VERSION 5.7 ;
  NOWIREEXTENSIONATPIN ON ;
  DIVIDERCHAR "/" ;
  BUSBITCHARS "[]" ;
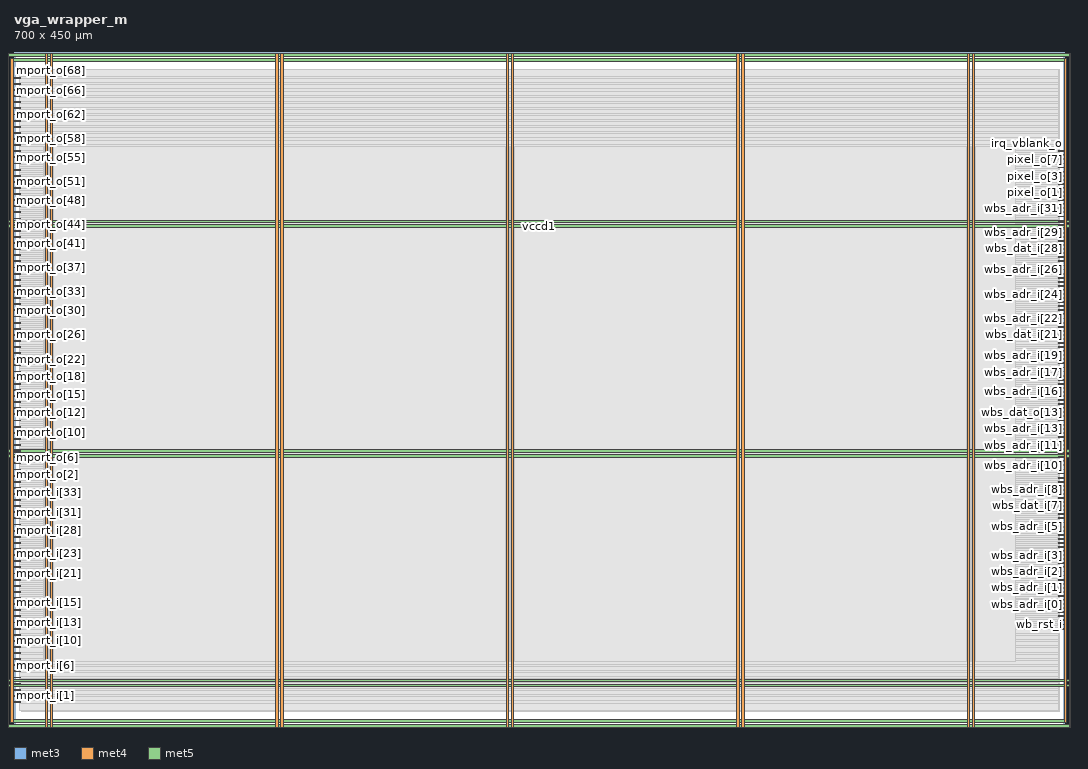
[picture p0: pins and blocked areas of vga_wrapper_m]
MACRO vga_wrapper_m
  CLASS BLOCK ;
  FOREIGN vga_wrapper_m ;
  ORIGIN 0.000 0.000 ;
  SIZE 700.000 BY 450.000 ;
  PIN hsync_o
    DIRECTION OUTPUT TRISTATE ;
    USE SIGNAL ;
    ANTENNADIFFAREA 0.445500 ;
    PORT
      LAYER met3 ;
        RECT 696.000 375.400 700.000 376.000 ;
    END
  END hsync_o
  PIN irq_hblank_o
    DIRECTION OUTPUT TRISTATE ;
    USE SIGNAL ;
    ANTENNADIFFAREA 0.445500 ;
    PORT
      LAYER met3 ;
        RECT 696.000 380.840 700.000 381.440 ;
    END
  END irq_hblank_o
  PIN irq_vblank_o
    DIRECTION OUTPUT TRISTATE ;
    USE SIGNAL ;
    ANTENNADIFFAREA 0.445500 ;
    PORT
      LAYER met3 ;
        RECT 696.000 383.560 700.000 384.160 ;
    END
  END irq_vblank_o
  PIN mport_i[0]
    DIRECTION INPUT ;
    USE SIGNAL ;
    ANTENNAGATEAREA 0.495000 ;
    PORT
      LAYER met3 ;
        RECT 0.000 16.360 4.000 16.960 ;
    END
  END mport_i[0]
  PIN mport_i[10]
    DIRECTION INPUT ;
    USE SIGNAL ;
    ANTENNAGATEAREA 0.247500 ;
    PORT
      LAYER met3 ;
        RECT 0.000 57.160 4.000 57.760 ;
    END
  END mport_i[10]
  PIN mport_i[11]
    DIRECTION INPUT ;
    USE SIGNAL ;
    ANTENNAGATEAREA 0.247500 ;
    PORT
      LAYER met3 ;
        RECT 0.000 61.240 4.000 61.840 ;
    END
  END mport_i[11]
  PIN mport_i[12]
    DIRECTION INPUT ;
    USE SIGNAL ;
    ANTENNAGATEAREA 0.426000 ;
    PORT
      LAYER met3 ;
        RECT 0.000 65.320 4.000 65.920 ;
    END
  END mport_i[12]
  PIN mport_i[13]
    DIRECTION INPUT ;
    USE SIGNAL ;
    ANTENNAGATEAREA 0.495000 ;
    PORT
      LAYER met3 ;
        RECT 0.000 69.400 4.000 70.000 ;
    END
  END mport_i[13]
  PIN mport_i[14]
    DIRECTION INPUT ;
    USE SIGNAL ;
    ANTENNAGATEAREA 0.247500 ;
    PORT
      LAYER met3 ;
        RECT 0.000 73.480 4.000 74.080 ;
    END
  END mport_i[14]
  PIN mport_i[15]
    DIRECTION INPUT ;
    USE SIGNAL ;
    ANTENNAGATEAREA 0.196500 ;
    PORT
      LAYER met3 ;
        RECT 0.000 77.560 4.000 78.160 ;
    END
  END mport_i[15]
  PIN mport_i[16]
    DIRECTION INPUT ;
    USE SIGNAL ;
    ANTENNAGATEAREA 0.196500 ;
    PORT
      LAYER met3 ;
        RECT 0.000 81.640 4.000 82.240 ;
    END
  END mport_i[16]
  PIN mport_i[17]
    DIRECTION INPUT ;
    USE SIGNAL ;
    ANTENNAGATEAREA 0.196500 ;
    PORT
      LAYER met3 ;
        RECT 0.000 85.720 4.000 86.320 ;
    END
  END mport_i[17]
  PIN mport_i[18]
    DIRECTION INPUT ;
    USE SIGNAL ;
    ANTENNAGATEAREA 0.196500 ;
    PORT
      LAYER met3 ;
        RECT 0.000 89.800 4.000 90.400 ;
    END
  END mport_i[18]
  PIN mport_i[19]
    DIRECTION INPUT ;
    USE SIGNAL ;
    ANTENNAGATEAREA 0.196500 ;
    PORT
      LAYER met3 ;
        RECT 0.000 93.880 4.000 94.480 ;
    END
  END mport_i[19]
  PIN mport_i[1]
    DIRECTION INPUT ;
    USE SIGNAL ;
    ANTENNAGATEAREA 0.426000 ;
    PORT
      LAYER met3 ;
        RECT 0.000 20.440 4.000 21.040 ;
    END
  END mport_i[1]
  PIN mport_i[20]
    DIRECTION INPUT ;
    USE SIGNAL ;
    ANTENNAGATEAREA 0.247500 ;
    PORT
      LAYER met3 ;
        RECT 0.000 97.960 4.000 98.560 ;
    END
  END mport_i[20]
  PIN mport_i[21]
    DIRECTION INPUT ;
    USE SIGNAL ;
    ANTENNAGATEAREA 0.196500 ;
    PORT
      LAYER met3 ;
        RECT 0.000 102.040 4.000 102.640 ;
    END
  END mport_i[21]
  PIN mport_i[22]
    DIRECTION INPUT ;
    USE SIGNAL ;
    ANTENNAGATEAREA 0.196500 ;
    PORT
      LAYER met3 ;
        RECT 0.000 106.120 4.000 106.720 ;
    END
  END mport_i[22]
  PIN mport_i[23]
    DIRECTION INPUT ;
    USE SIGNAL ;
    ANTENNAGATEAREA 0.426000 ;
    PORT
      LAYER met3 ;
        RECT 0.000 110.200 4.000 110.800 ;
    END
  END mport_i[23]
  PIN mport_i[24]
    DIRECTION INPUT ;
    USE SIGNAL ;
    ANTENNAGATEAREA 0.213000 ;
    PORT
      LAYER met3 ;
        RECT 0.000 114.280 4.000 114.880 ;
    END
  END mport_i[24]
  PIN mport_i[25]
    DIRECTION INPUT ;
    USE SIGNAL ;
    ANTENNAGATEAREA 0.426000 ;
    PORT
      LAYER met3 ;
        RECT 0.000 118.360 4.000 118.960 ;
    END
  END mport_i[25]
  PIN mport_i[26]
    DIRECTION INPUT ;
    USE SIGNAL ;
    ANTENNAGATEAREA 0.426000 ;
    PORT
      LAYER met3 ;
        RECT 0.000 122.440 4.000 123.040 ;
    END
  END mport_i[26]
  PIN mport_i[27]
    DIRECTION INPUT ;
    USE SIGNAL ;
    ANTENNAGATEAREA 0.196500 ;
    PORT
      LAYER met3 ;
        RECT 0.000 126.520 4.000 127.120 ;
    END
  END mport_i[27]
  PIN mport_i[28]
    DIRECTION INPUT ;
    USE SIGNAL ;
    ANTENNAGATEAREA 0.426000 ;
    PORT
      LAYER met3 ;
        RECT 0.000 130.600 4.000 131.200 ;
    END
  END mport_i[28]
  PIN mport_i[29]
    DIRECTION INPUT ;
    USE SIGNAL ;
    ANTENNAGATEAREA 0.196500 ;
    PORT
      LAYER met3 ;
        RECT 0.000 134.680 4.000 135.280 ;
    END
  END mport_i[29]
  PIN mport_i[2]
    DIRECTION INPUT ;
    USE SIGNAL ;
    ANTENNAGATEAREA 0.126000 ;
    PORT
      LAYER met3 ;
        RECT 0.000 24.520 4.000 25.120 ;
    END
  END mport_i[2]
  PIN mport_i[30]
    DIRECTION INPUT ;
    USE SIGNAL ;
    ANTENNAGATEAREA 0.126000 ;
    PORT
      LAYER met3 ;
        RECT 0.000 138.760 4.000 139.360 ;
    END
  END mport_i[30]
  PIN mport_i[31]
    DIRECTION INPUT ;
    USE SIGNAL ;
    ANTENNAGATEAREA 0.196500 ;
    PORT
      LAYER met3 ;
        RECT 0.000 142.840 4.000 143.440 ;
    END
  END mport_i[31]
  PIN mport_i[32]
    DIRECTION INPUT ;
    USE SIGNAL ;
    ANTENNAGATEAREA 0.247500 ;
    PORT
      LAYER met3 ;
        RECT 0.000 146.920 4.000 147.520 ;
    END
  END mport_i[32]
  PIN mport_i[33]
    DIRECTION INPUT ;
    USE SIGNAL ;
    ANTENNAGATEAREA 0.213000 ;
    PORT
      LAYER met3 ;
        RECT 0.000 151.000 4.000 151.600 ;
    END
  END mport_i[33]
  PIN mport_i[3]
    DIRECTION INPUT ;
    USE SIGNAL ;
    ANTENNAGATEAREA 0.196500 ;
    PORT
      LAYER met3 ;
        RECT 0.000 28.600 4.000 29.200 ;
    END
  END mport_i[3]
  PIN mport_i[4]
    DIRECTION INPUT ;
    USE SIGNAL ;
    ANTENNAGATEAREA 0.196500 ;
    PORT
      LAYER met3 ;
        RECT 0.000 32.680 4.000 33.280 ;
    END
  END mport_i[4]
  PIN mport_i[5]
    DIRECTION INPUT ;
    USE SIGNAL ;
    ANTENNAGATEAREA 0.495000 ;
    PORT
      LAYER met3 ;
        RECT 0.000 36.760 4.000 37.360 ;
    END
  END mport_i[5]
  PIN mport_i[6]
    DIRECTION INPUT ;
    USE SIGNAL ;
    ANTENNAGATEAREA 0.196500 ;
    PORT
      LAYER met3 ;
        RECT 0.000 40.840 4.000 41.440 ;
    END
  END mport_i[6]
  PIN mport_i[7]
    DIRECTION INPUT ;
    USE SIGNAL ;
    ANTENNAGATEAREA 0.196500 ;
    PORT
      LAYER met3 ;
        RECT 0.000 44.920 4.000 45.520 ;
    END
  END mport_i[7]
  PIN mport_i[8]
    DIRECTION INPUT ;
    USE SIGNAL ;
    ANTENNAGATEAREA 0.247500 ;
    PORT
      LAYER met3 ;
        RECT 0.000 49.000 4.000 49.600 ;
    END
  END mport_i[8]
  PIN mport_i[9]
    DIRECTION INPUT ;
    USE SIGNAL ;
    ANTENNAGATEAREA 0.196500 ;
    PORT
      LAYER met3 ;
        RECT 0.000 53.080 4.000 53.680 ;
    END
  END mport_i[9]
  PIN mport_o[0]
    DIRECTION OUTPUT TRISTATE ;
    USE SIGNAL ;
    PORT
      LAYER met3 ;
        RECT 0.000 155.080 4.000 155.680 ;
    END
  END mport_o[0]
  PIN mport_o[10]
    DIRECTION OUTPUT TRISTATE ;
    USE SIGNAL ;
    PORT
      LAYER met3 ;
        RECT 0.000 195.880 4.000 196.480 ;
    END
  END mport_o[10]
  PIN mport_o[11]
    DIRECTION OUTPUT TRISTATE ;
    USE SIGNAL ;
    PORT
      LAYER met3 ;
        RECT 0.000 199.960 4.000 200.560 ;
    END
  END mport_o[11]
  PIN mport_o[12]
    DIRECTION OUTPUT TRISTATE ;
    USE SIGNAL ;
    PORT
      LAYER met3 ;
        RECT 0.000 204.040 4.000 204.640 ;
    END
  END mport_o[12]
  PIN mport_o[13]
    DIRECTION OUTPUT TRISTATE ;
    USE SIGNAL ;
    PORT
      LAYER met3 ;
        RECT 0.000 208.120 4.000 208.720 ;
    END
  END mport_o[13]
  PIN mport_o[14]
    DIRECTION OUTPUT TRISTATE ;
    USE SIGNAL ;
    PORT
      LAYER met3 ;
        RECT 0.000 212.200 4.000 212.800 ;
    END
  END mport_o[14]
  PIN mport_o[15]
    DIRECTION OUTPUT TRISTATE ;
    USE SIGNAL ;
    PORT
      LAYER met3 ;
        RECT 0.000 216.280 4.000 216.880 ;
    END
  END mport_o[15]
  PIN mport_o[16]
    DIRECTION OUTPUT TRISTATE ;
    USE SIGNAL ;
    PORT
      LAYER met3 ;
        RECT 0.000 220.360 4.000 220.960 ;
    END
  END mport_o[16]
  PIN mport_o[17]
    DIRECTION OUTPUT TRISTATE ;
    USE SIGNAL ;
    PORT
      LAYER met3 ;
        RECT 0.000 224.440 4.000 225.040 ;
    END
  END mport_o[17]
  PIN mport_o[18]
    DIRECTION OUTPUT TRISTATE ;
    USE SIGNAL ;
    PORT
      LAYER met3 ;
        RECT 0.000 228.520 4.000 229.120 ;
    END
  END mport_o[18]
  PIN mport_o[19]
    DIRECTION OUTPUT TRISTATE ;
    USE SIGNAL ;
    PORT
      LAYER met3 ;
        RECT 0.000 232.600 4.000 233.200 ;
    END
  END mport_o[19]
  PIN mport_o[1]
    DIRECTION OUTPUT TRISTATE ;
    USE SIGNAL ;
    PORT
      LAYER met3 ;
        RECT 0.000 159.160 4.000 159.760 ;
    END
  END mport_o[1]
  PIN mport_o[20]
    DIRECTION OUTPUT TRISTATE ;
    USE SIGNAL ;
    PORT
      LAYER met3 ;
        RECT 0.000 236.680 4.000 237.280 ;
    END
  END mport_o[20]
  PIN mport_o[21]
    DIRECTION OUTPUT TRISTATE ;
    USE SIGNAL ;
    PORT
      LAYER met3 ;
        RECT 0.000 240.760 4.000 241.360 ;
    END
  END mport_o[21]
  PIN mport_o[22]
    DIRECTION OUTPUT TRISTATE ;
    USE SIGNAL ;
    PORT
      LAYER met3 ;
        RECT 0.000 244.840 4.000 245.440 ;
    END
  END mport_o[22]
  PIN mport_o[23]
    DIRECTION OUTPUT TRISTATE ;
    USE SIGNAL ;
    PORT
      LAYER met3 ;
        RECT 0.000 248.920 4.000 249.520 ;
    END
  END mport_o[23]
  PIN mport_o[24]
    DIRECTION OUTPUT TRISTATE ;
    USE SIGNAL ;
    PORT
      LAYER met3 ;
        RECT 0.000 253.000 4.000 253.600 ;
    END
  END mport_o[24]
  PIN mport_o[25]
    DIRECTION OUTPUT TRISTATE ;
    USE SIGNAL ;
    PORT
      LAYER met3 ;
        RECT 0.000 257.080 4.000 257.680 ;
    END
  END mport_o[25]
  PIN mport_o[26]
    DIRECTION OUTPUT TRISTATE ;
    USE SIGNAL ;
    PORT
      LAYER met3 ;
        RECT 0.000 261.160 4.000 261.760 ;
    END
  END mport_o[26]
  PIN mport_o[27]
    DIRECTION OUTPUT TRISTATE ;
    USE SIGNAL ;
    PORT
      LAYER met3 ;
        RECT 0.000 265.240 4.000 265.840 ;
    END
  END mport_o[27]
  PIN mport_o[28]
    DIRECTION OUTPUT TRISTATE ;
    USE SIGNAL ;
    PORT
      LAYER met3 ;
        RECT 0.000 269.320 4.000 269.920 ;
    END
  END mport_o[28]
  PIN mport_o[29]
    DIRECTION OUTPUT TRISTATE ;
    USE SIGNAL ;
    PORT
      LAYER met3 ;
        RECT 0.000 273.400 4.000 274.000 ;
    END
  END mport_o[29]
  PIN mport_o[2]
    DIRECTION OUTPUT TRISTATE ;
    USE SIGNAL ;
    PORT
      LAYER met3 ;
        RECT 0.000 163.240 4.000 163.840 ;
    END
  END mport_o[2]
  PIN mport_o[30]
    DIRECTION OUTPUT TRISTATE ;
    USE SIGNAL ;
    PORT
      LAYER met3 ;
        RECT 0.000 277.480 4.000 278.080 ;
    END
  END mport_o[30]
  PIN mport_o[31]
    DIRECTION OUTPUT TRISTATE ;
    USE SIGNAL ;
    PORT
      LAYER met3 ;
        RECT 0.000 281.560 4.000 282.160 ;
    END
  END mport_o[31]
  PIN mport_o[32]
    DIRECTION OUTPUT TRISTATE ;
    USE SIGNAL ;
    ANTENNADIFFAREA 0.795200 ;
    PORT
      LAYER met3 ;
        RECT 0.000 285.640 4.000 286.240 ;
    END
  END mport_o[32]
  PIN mport_o[33]
    DIRECTION OUTPUT TRISTATE ;
    USE SIGNAL ;
    ANTENNADIFFAREA 0.795200 ;
    PORT
      LAYER met3 ;
        RECT 0.000 289.720 4.000 290.320 ;
    END
  END mport_o[33]
  PIN mport_o[34]
    DIRECTION OUTPUT TRISTATE ;
    USE SIGNAL ;
    ANTENNADIFFAREA 0.795200 ;
    PORT
      LAYER met3 ;
        RECT 0.000 293.800 4.000 294.400 ;
    END
  END mport_o[34]
  PIN mport_o[35]
    DIRECTION OUTPUT TRISTATE ;
    USE SIGNAL ;
    ANTENNADIFFAREA 0.795200 ;
    PORT
      LAYER met3 ;
        RECT 0.000 297.880 4.000 298.480 ;
    END
  END mport_o[35]
  PIN mport_o[36]
    DIRECTION OUTPUT TRISTATE ;
    USE SIGNAL ;
    ANTENNADIFFAREA 0.795200 ;
    PORT
      LAYER met3 ;
        RECT 0.000 301.960 4.000 302.560 ;
    END
  END mport_o[36]
  PIN mport_o[37]
    DIRECTION OUTPUT TRISTATE ;
    USE SIGNAL ;
    ANTENNADIFFAREA 0.795200 ;
    PORT
      LAYER met3 ;
        RECT 0.000 306.040 4.000 306.640 ;
    END
  END mport_o[37]
  PIN mport_o[38]
    DIRECTION OUTPUT TRISTATE ;
    USE SIGNAL ;
    ANTENNADIFFAREA 0.795200 ;
    PORT
      LAYER met3 ;
        RECT 0.000 310.120 4.000 310.720 ;
    END
  END mport_o[38]
  PIN mport_o[39]
    DIRECTION OUTPUT TRISTATE ;
    USE SIGNAL ;
    ANTENNADIFFAREA 0.795200 ;
    PORT
      LAYER met3 ;
        RECT 0.000 314.200 4.000 314.800 ;
    END
  END mport_o[39]
  PIN mport_o[3]
    DIRECTION OUTPUT TRISTATE ;
    USE SIGNAL ;
    PORT
      LAYER met3 ;
        RECT 0.000 167.320 4.000 167.920 ;
    END
  END mport_o[3]
  PIN mport_o[40]
    DIRECTION OUTPUT TRISTATE ;
    USE SIGNAL ;
    ANTENNADIFFAREA 0.795200 ;
    PORT
      LAYER met3 ;
        RECT 0.000 318.280 4.000 318.880 ;
    END
  END mport_o[40]
  PIN mport_o[41]
    DIRECTION OUTPUT TRISTATE ;
    USE SIGNAL ;
    ANTENNADIFFAREA 0.795200 ;
    PORT
      LAYER met3 ;
        RECT 0.000 322.360 4.000 322.960 ;
    END
  END mport_o[41]
  PIN mport_o[42]
    DIRECTION OUTPUT TRISTATE ;
    USE SIGNAL ;
    ANTENNADIFFAREA 0.795200 ;
    PORT
      LAYER met3 ;
        RECT 0.000 326.440 4.000 327.040 ;
    END
  END mport_o[42]
  PIN mport_o[43]
    DIRECTION OUTPUT TRISTATE ;
    USE SIGNAL ;
    ANTENNADIFFAREA 0.795200 ;
    PORT
      LAYER met3 ;
        RECT 0.000 330.520 4.000 331.120 ;
    END
  END mport_o[43]
  PIN mport_o[44]
    DIRECTION OUTPUT TRISTATE ;
    USE SIGNAL ;
    ANTENNADIFFAREA 0.795200 ;
    PORT
      LAYER met3 ;
        RECT 0.000 334.600 4.000 335.200 ;
    END
  END mport_o[44]
  PIN mport_o[45]
    DIRECTION OUTPUT TRISTATE ;
    USE SIGNAL ;
    ANTENNADIFFAREA 0.795200 ;
    PORT
      LAYER met3 ;
        RECT 0.000 338.680 4.000 339.280 ;
    END
  END mport_o[45]
  PIN mport_o[46]
    DIRECTION OUTPUT TRISTATE ;
    USE SIGNAL ;
    ANTENNADIFFAREA 0.795200 ;
    PORT
      LAYER met3 ;
        RECT 0.000 342.760 4.000 343.360 ;
    END
  END mport_o[46]
  PIN mport_o[47]
    DIRECTION OUTPUT TRISTATE ;
    USE SIGNAL ;
    ANTENNADIFFAREA 0.795200 ;
    PORT
      LAYER met3 ;
        RECT 0.000 346.840 4.000 347.440 ;
    END
  END mport_o[47]
  PIN mport_o[48]
    DIRECTION OUTPUT TRISTATE ;
    USE SIGNAL ;
    ANTENNADIFFAREA 0.795200 ;
    PORT
      LAYER met3 ;
        RECT 0.000 350.920 4.000 351.520 ;
    END
  END mport_o[48]
  PIN mport_o[49]
    DIRECTION OUTPUT TRISTATE ;
    USE SIGNAL ;
    ANTENNADIFFAREA 0.795200 ;
    PORT
      LAYER met3 ;
        RECT 0.000 355.000 4.000 355.600 ;
    END
  END mport_o[49]
  PIN mport_o[4]
    DIRECTION OUTPUT TRISTATE ;
    USE SIGNAL ;
    PORT
      LAYER met3 ;
        RECT 0.000 171.400 4.000 172.000 ;
    END
  END mport_o[4]
  PIN mport_o[50]
    DIRECTION OUTPUT TRISTATE ;
    USE SIGNAL ;
    ANTENNADIFFAREA 0.795200 ;
    PORT
      LAYER met3 ;
        RECT 0.000 359.080 4.000 359.680 ;
    END
  END mport_o[50]
  PIN mport_o[51]
    DIRECTION OUTPUT TRISTATE ;
    USE SIGNAL ;
    ANTENNADIFFAREA 0.795200 ;
    PORT
      LAYER met3 ;
        RECT 0.000 363.160 4.000 363.760 ;
    END
  END mport_o[51]
  PIN mport_o[52]
    DIRECTION OUTPUT TRISTATE ;
    USE SIGNAL ;
    ANTENNADIFFAREA 0.795200 ;
    PORT
      LAYER met3 ;
        RECT 0.000 367.240 4.000 367.840 ;
    END
  END mport_o[52]
  PIN mport_o[53]
    DIRECTION OUTPUT TRISTATE ;
    USE SIGNAL ;
    ANTENNADIFFAREA 0.795200 ;
    PORT
      LAYER met3 ;
        RECT 0.000 371.320 4.000 371.920 ;
    END
  END mport_o[53]
  PIN mport_o[54]
    DIRECTION OUTPUT TRISTATE ;
    USE SIGNAL ;
    ANTENNADIFFAREA 0.795200 ;
    PORT
      LAYER met3 ;
        RECT 0.000 375.400 4.000 376.000 ;
    END
  END mport_o[54]
  PIN mport_o[55]
    DIRECTION OUTPUT TRISTATE ;
    USE SIGNAL ;
    ANTENNADIFFAREA 0.795200 ;
    PORT
      LAYER met3 ;
        RECT 0.000 379.480 4.000 380.080 ;
    END
  END mport_o[55]
  PIN mport_o[56]
    DIRECTION OUTPUT TRISTATE ;
    USE SIGNAL ;
    ANTENNADIFFAREA 0.795200 ;
    PORT
      LAYER met3 ;
        RECT 0.000 383.560 4.000 384.160 ;
    END
  END mport_o[56]
  PIN mport_o[57]
    DIRECTION OUTPUT TRISTATE ;
    USE SIGNAL ;
    ANTENNADIFFAREA 0.795200 ;
    PORT
      LAYER met3 ;
        RECT 0.000 387.640 4.000 388.240 ;
    END
  END mport_o[57]
  PIN mport_o[58]
    DIRECTION OUTPUT TRISTATE ;
    USE SIGNAL ;
    ANTENNADIFFAREA 0.795200 ;
    PORT
      LAYER met3 ;
        RECT 0.000 391.720 4.000 392.320 ;
    END
  END mport_o[58]
  PIN mport_o[59]
    DIRECTION OUTPUT TRISTATE ;
    USE SIGNAL ;
    ANTENNADIFFAREA 0.795200 ;
    PORT
      LAYER met3 ;
        RECT 0.000 395.800 4.000 396.400 ;
    END
  END mport_o[59]
  PIN mport_o[5]
    DIRECTION OUTPUT TRISTATE ;
    USE SIGNAL ;
    PORT
      LAYER met3 ;
        RECT 0.000 175.480 4.000 176.080 ;
    END
  END mport_o[5]
  PIN mport_o[60]
    DIRECTION OUTPUT TRISTATE ;
    USE SIGNAL ;
    ANTENNADIFFAREA 0.795200 ;
    PORT
      LAYER met3 ;
        RECT 0.000 399.880 4.000 400.480 ;
    END
  END mport_o[60]
  PIN mport_o[61]
    DIRECTION OUTPUT TRISTATE ;
    USE SIGNAL ;
    ANTENNADIFFAREA 0.795200 ;
    PORT
      LAYER met3 ;
        RECT 0.000 403.960 4.000 404.560 ;
    END
  END mport_o[61]
  PIN mport_o[62]
    DIRECTION OUTPUT TRISTATE ;
    USE SIGNAL ;
    ANTENNADIFFAREA 0.795200 ;
    PORT
      LAYER met3 ;
        RECT 0.000 408.040 4.000 408.640 ;
    END
  END mport_o[62]
  PIN mport_o[63]
    DIRECTION OUTPUT TRISTATE ;
    USE SIGNAL ;
    ANTENNADIFFAREA 0.795200 ;
    PORT
      LAYER met3 ;
        RECT 0.000 412.120 4.000 412.720 ;
    END
  END mport_o[63]
  PIN mport_o[64]
    DIRECTION OUTPUT TRISTATE ;
    USE SIGNAL ;
    ANTENNADIFFAREA 0.795200 ;
    PORT
      LAYER met3 ;
        RECT 0.000 416.200 4.000 416.800 ;
    END
  END mport_o[64]
  PIN mport_o[65]
    DIRECTION OUTPUT TRISTATE ;
    USE SIGNAL ;
    ANTENNADIFFAREA 0.795200 ;
    PORT
      LAYER met3 ;
        RECT 0.000 420.280 4.000 420.880 ;
    END
  END mport_o[65]
  PIN mport_o[66]
    DIRECTION OUTPUT TRISTATE ;
    USE SIGNAL ;
    ANTENNADIFFAREA 0.795200 ;
    PORT
      LAYER met3 ;
        RECT 0.000 424.360 4.000 424.960 ;
    END
  END mport_o[66]
  PIN mport_o[67]
    DIRECTION OUTPUT TRISTATE ;
    USE SIGNAL ;
    ANTENNADIFFAREA 0.795200 ;
    PORT
      LAYER met3 ;
        RECT 0.000 428.440 4.000 429.040 ;
    END
  END mport_o[67]
  PIN mport_o[68]
    DIRECTION OUTPUT TRISTATE ;
    USE SIGNAL ;
    PORT
      LAYER met3 ;
        RECT 0.000 432.520 4.000 433.120 ;
    END
  END mport_o[68]
  PIN mport_o[6]
    DIRECTION OUTPUT TRISTATE ;
    USE SIGNAL ;
    PORT
      LAYER met3 ;
        RECT 0.000 179.560 4.000 180.160 ;
    END
  END mport_o[6]
  PIN mport_o[7]
    DIRECTION OUTPUT TRISTATE ;
    USE SIGNAL ;
    PORT
      LAYER met3 ;
        RECT 0.000 183.640 4.000 184.240 ;
    END
  END mport_o[7]
  PIN mport_o[8]
    DIRECTION OUTPUT TRISTATE ;
    USE SIGNAL ;
    PORT
      LAYER met3 ;
        RECT 0.000 187.720 4.000 188.320 ;
    END
  END mport_o[8]
  PIN mport_o[9]
    DIRECTION OUTPUT TRISTATE ;
    USE SIGNAL ;
    PORT
      LAYER met3 ;
        RECT 0.000 191.800 4.000 192.400 ;
    END
  END mport_o[9]
  PIN pixel_o[0]
    DIRECTION OUTPUT TRISTATE ;
    USE SIGNAL ;
    ANTENNADIFFAREA 0.445500 ;
    PORT
      LAYER met3 ;
        RECT 696.000 353.640 700.000 354.240 ;
    END
  END pixel_o[0]
  PIN pixel_o[1]
    DIRECTION OUTPUT TRISTATE ;
    USE SIGNAL ;
    ANTENNADIFFAREA 0.445500 ;
    PORT
      LAYER met3 ;
        RECT 696.000 356.360 700.000 356.960 ;
    END
  END pixel_o[1]
  PIN pixel_o[2]
    DIRECTION OUTPUT TRISTATE ;
    USE SIGNAL ;
    ANTENNADIFFAREA 0.445500 ;
    PORT
      LAYER met3 ;
        RECT 696.000 359.080 700.000 359.680 ;
    END
  END pixel_o[2]
  PIN pixel_o[3]
    DIRECTION OUTPUT TRISTATE ;
    USE SIGNAL ;
    ANTENNADIFFAREA 0.795200 ;
    PORT
      LAYER met3 ;
        RECT 696.000 361.800 700.000 362.400 ;
    END
  END pixel_o[3]
  PIN pixel_o[4]
    DIRECTION OUTPUT TRISTATE ;
    USE SIGNAL ;
    ANTENNADIFFAREA 0.795200 ;
    PORT
      LAYER met3 ;
        RECT 696.000 364.520 700.000 365.120 ;
    END
  END pixel_o[4]
  PIN pixel_o[5]
    DIRECTION OUTPUT TRISTATE ;
    USE SIGNAL ;
    ANTENNADIFFAREA 0.445500 ;
    PORT
      LAYER met3 ;
        RECT 696.000 367.240 700.000 367.840 ;
    END
  END pixel_o[5]
  PIN pixel_o[6]
    DIRECTION OUTPUT TRISTATE ;
    USE SIGNAL ;
    ANTENNADIFFAREA 0.795200 ;
    PORT
      LAYER met3 ;
        RECT 696.000 369.960 700.000 370.560 ;
    END
  END pixel_o[6]
  PIN pixel_o[7]
    DIRECTION OUTPUT TRISTATE ;
    USE SIGNAL ;
    ANTENNADIFFAREA 0.445500 ;
    PORT
      LAYER met3 ;
        RECT 696.000 372.680 700.000 373.280 ;
    END
  END pixel_o[7]
  PIN vccd1
    DIRECTION INOUT ;
    USE POWER ;
    PORT
      LAYER met4 ;
        RECT -2.080 3.280 -0.480 445.520 ;
    END
    PORT
      LAYER met5 ;
        RECT -2.080 3.280 701.740 4.880 ;
    END
    PORT
      LAYER met5 ;
        RECT -2.080 443.920 701.740 445.520 ;
    END
    PORT
      LAYER met4 ;
        RECT 700.140 3.280 701.740 445.520 ;
    END
    PORT
      LAYER met4 ;
        RECT 21.040 -0.020 22.640 448.820 ;
    END
    PORT
      LAYER met4 ;
        RECT 174.640 -0.020 176.240 448.820 ;
    END
    PORT
      LAYER met4 ;
        RECT 328.240 -0.020 329.840 448.820 ;
    END
    PORT
      LAYER met4 ;
        RECT 481.840 -0.020 483.440 448.820 ;
    END
    PORT
      LAYER met4 ;
        RECT 635.440 -0.020 637.040 448.820 ;
    END
    PORT
      LAYER met5 ;
        RECT -5.380 26.730 705.040 28.330 ;
    END
    PORT
      LAYER met5 ;
        RECT -5.380 179.910 705.040 181.510 ;
    END
    PORT
      LAYER met5 ;
        RECT -5.380 333.090 705.040 334.690 ;
    END
  END vccd1
  PIN vssd1
    DIRECTION INOUT ;
    USE GROUND ;
    PORT
      LAYER met4 ;
        RECT -5.380 -0.020 -3.780 448.820 ;
    END
    PORT
      LAYER met5 ;
        RECT -5.380 -0.020 705.040 1.580 ;
    END
    PORT
      LAYER met5 ;
        RECT -5.380 447.220 705.040 448.820 ;
    END
    PORT
      LAYER met4 ;
        RECT 703.440 -0.020 705.040 448.820 ;
    END
    PORT
      LAYER met4 ;
        RECT 24.340 -0.020 25.940 448.820 ;
    END
    PORT
      LAYER met4 ;
        RECT 177.940 -0.020 179.540 448.820 ;
    END
    PORT
      LAYER met4 ;
        RECT 331.540 -0.020 333.140 448.820 ;
    END
    PORT
      LAYER met4 ;
        RECT 485.140 -0.020 486.740 448.820 ;
    END
    PORT
      LAYER met4 ;
        RECT 638.740 -0.020 640.340 448.820 ;
    END
    PORT
      LAYER met5 ;
        RECT -5.380 30.030 705.040 31.630 ;
    END
    PORT
      LAYER met5 ;
        RECT -5.380 183.210 705.040 184.810 ;
    END
    PORT
      LAYER met5 ;
        RECT -5.380 336.390 705.040 337.990 ;
    END
  END vssd1
  PIN vsync_o
    DIRECTION OUTPUT TRISTATE ;
    USE SIGNAL ;
    ANTENNADIFFAREA 0.795200 ;
    PORT
      LAYER met3 ;
        RECT 696.000 378.120 700.000 378.720 ;
    END
  END vsync_o
  PIN wb_clk_i
    DIRECTION INPUT ;
    USE SIGNAL ;
    ANTENNAGATEAREA 0.852000 ;
    PORT
      LAYER met3 ;
        RECT 696.000 65.320 700.000 65.920 ;
    END
  END wb_clk_i
  PIN wb_rst_i
    DIRECTION INPUT ;
    USE SIGNAL ;
    ANTENNAGATEAREA 0.213000 ;
    PORT
      LAYER met3 ;
        RECT 696.000 68.040 700.000 68.640 ;
    END
  END wb_rst_i
  PIN wbs_ack_o
    DIRECTION OUTPUT TRISTATE ;
    USE SIGNAL ;
    ANTENNADIFFAREA 0.795200 ;
    PORT
      LAYER met3 ;
        RECT 696.000 70.760 700.000 71.360 ;
    END
  END wbs_ack_o
  PIN wbs_adr_i[0]
    DIRECTION INPUT ;
    USE SIGNAL ;
    PORT
      LAYER met3 ;
        RECT 696.000 81.640 700.000 82.240 ;
    END
  END wbs_adr_i[0]
  PIN wbs_adr_i[10]
    DIRECTION INPUT ;
    USE SIGNAL ;
    PORT
      LAYER met3 ;
        RECT 696.000 174.120 700.000 174.720 ;
    END
  END wbs_adr_i[10]
  PIN wbs_adr_i[11]
    DIRECTION INPUT ;
    USE SIGNAL ;
    PORT
      LAYER met3 ;
        RECT 696.000 182.280 700.000 182.880 ;
    END
  END wbs_adr_i[11]
  PIN wbs_adr_i[12]
    DIRECTION INPUT ;
    USE SIGNAL ;
    PORT
      LAYER met3 ;
        RECT 696.000 190.440 700.000 191.040 ;
    END
  END wbs_adr_i[12]
  PIN wbs_adr_i[13]
    DIRECTION INPUT ;
    USE SIGNAL ;
    PORT
      LAYER met3 ;
        RECT 696.000 198.600 700.000 199.200 ;
    END
  END wbs_adr_i[13]
  PIN wbs_adr_i[14]
    DIRECTION INPUT ;
    USE SIGNAL ;
    PORT
      LAYER met3 ;
        RECT 696.000 206.760 700.000 207.360 ;
    END
  END wbs_adr_i[14]
  PIN wbs_adr_i[15]
    DIRECTION INPUT ;
    USE SIGNAL ;
    PORT
      LAYER met3 ;
        RECT 696.000 214.920 700.000 215.520 ;
    END
  END wbs_adr_i[15]
  PIN wbs_adr_i[16]
    DIRECTION INPUT ;
    USE SIGNAL ;
    PORT
      LAYER met3 ;
        RECT 696.000 223.080 700.000 223.680 ;
    END
  END wbs_adr_i[16]
  PIN wbs_adr_i[17]
    DIRECTION INPUT ;
    USE SIGNAL ;
    PORT
      LAYER met3 ;
        RECT 696.000 231.240 700.000 231.840 ;
    END
  END wbs_adr_i[17]
  PIN wbs_adr_i[18]
    DIRECTION INPUT ;
    USE SIGNAL ;
    PORT
      LAYER met3 ;
        RECT 696.000 239.400 700.000 240.000 ;
    END
  END wbs_adr_i[18]
  PIN wbs_adr_i[19]
    DIRECTION INPUT ;
    USE SIGNAL ;
    PORT
      LAYER met3 ;
        RECT 696.000 247.560 700.000 248.160 ;
    END
  END wbs_adr_i[19]
  PIN wbs_adr_i[1]
    DIRECTION INPUT ;
    USE SIGNAL ;
    PORT
      LAYER met3 ;
        RECT 696.000 92.520 700.000 93.120 ;
    END
  END wbs_adr_i[1]
  PIN wbs_adr_i[20]
    DIRECTION INPUT ;
    USE SIGNAL ;
    PORT
      LAYER met3 ;
        RECT 696.000 255.720 700.000 256.320 ;
    END
  END wbs_adr_i[20]
  PIN wbs_adr_i[21]
    DIRECTION INPUT ;
    USE SIGNAL ;
    PORT
      LAYER met3 ;
        RECT 696.000 263.880 700.000 264.480 ;
    END
  END wbs_adr_i[21]
  PIN wbs_adr_i[22]
    DIRECTION INPUT ;
    USE SIGNAL ;
    PORT
      LAYER met3 ;
        RECT 696.000 272.040 700.000 272.640 ;
    END
  END wbs_adr_i[22]
  PIN wbs_adr_i[23]
    DIRECTION INPUT ;
    USE SIGNAL ;
    PORT
      LAYER met3 ;
        RECT 696.000 280.200 700.000 280.800 ;
    END
  END wbs_adr_i[23]
  PIN wbs_adr_i[24]
    DIRECTION INPUT ;
    USE SIGNAL ;
    PORT
      LAYER met3 ;
        RECT 696.000 288.360 700.000 288.960 ;
    END
  END wbs_adr_i[24]
  PIN wbs_adr_i[25]
    DIRECTION INPUT ;
    USE SIGNAL ;
    PORT
      LAYER met3 ;
        RECT 696.000 296.520 700.000 297.120 ;
    END
  END wbs_adr_i[25]
  PIN wbs_adr_i[26]
    DIRECTION INPUT ;
    USE SIGNAL ;
    PORT
      LAYER met3 ;
        RECT 696.000 304.680 700.000 305.280 ;
    END
  END wbs_adr_i[26]
  PIN wbs_adr_i[27]
    DIRECTION INPUT ;
    USE SIGNAL ;
    PORT
      LAYER met3 ;
        RECT 696.000 312.840 700.000 313.440 ;
    END
  END wbs_adr_i[27]
  PIN wbs_adr_i[28]
    DIRECTION INPUT ;
    USE SIGNAL ;
    PORT
      LAYER met3 ;
        RECT 696.000 321.000 700.000 321.600 ;
    END
  END wbs_adr_i[28]
  PIN wbs_adr_i[29]
    DIRECTION INPUT ;
    USE SIGNAL ;
    PORT
      LAYER met3 ;
        RECT 696.000 329.160 700.000 329.760 ;
    END
  END wbs_adr_i[29]
  PIN wbs_adr_i[2]
    DIRECTION INPUT ;
    USE SIGNAL ;
    ANTENNAGATEAREA 0.213000 ;
    PORT
      LAYER met3 ;
        RECT 696.000 103.400 700.000 104.000 ;
    END
  END wbs_adr_i[2]
  PIN wbs_adr_i[30]
    DIRECTION INPUT ;
    USE SIGNAL ;
    PORT
      LAYER met3 ;
        RECT 696.000 337.320 700.000 337.920 ;
    END
  END wbs_adr_i[30]
  PIN wbs_adr_i[31]
    DIRECTION INPUT ;
    USE SIGNAL ;
    PORT
      LAYER met3 ;
        RECT 696.000 345.480 700.000 346.080 ;
    END
  END wbs_adr_i[31]
  PIN wbs_adr_i[3]
    DIRECTION INPUT ;
    USE SIGNAL ;
    ANTENNAGATEAREA 0.213000 ;
    PORT
      LAYER met3 ;
        RECT 696.000 114.280 700.000 114.880 ;
    END
  END wbs_adr_i[3]
  PIN wbs_adr_i[4]
    DIRECTION INPUT ;
    USE SIGNAL ;
    ANTENNAGATEAREA 0.159000 ;
    PORT
      LAYER met3 ;
        RECT 696.000 125.160 700.000 125.760 ;
    END
  END wbs_adr_i[4]
  PIN wbs_adr_i[5]
    DIRECTION INPUT ;
    USE SIGNAL ;
    PORT
      LAYER met3 ;
        RECT 696.000 133.320 700.000 133.920 ;
    END
  END wbs_adr_i[5]
  PIN wbs_adr_i[6]
    DIRECTION INPUT ;
    USE SIGNAL ;
    PORT
      LAYER met3 ;
        RECT 696.000 141.480 700.000 142.080 ;
    END
  END wbs_adr_i[6]
  PIN wbs_adr_i[7]
    DIRECTION INPUT ;
    USE SIGNAL ;
    PORT
      LAYER met3 ;
        RECT 696.000 149.640 700.000 150.240 ;
    END
  END wbs_adr_i[7]
  PIN wbs_adr_i[8]
    DIRECTION INPUT ;
    USE SIGNAL ;
    PORT
      LAYER met3 ;
        RECT 696.000 157.800 700.000 158.400 ;
    END
  END wbs_adr_i[8]
  PIN wbs_adr_i[9]
    DIRECTION INPUT ;
    USE SIGNAL ;
    PORT
      LAYER met3 ;
        RECT 696.000 165.960 700.000 166.560 ;
    END
  END wbs_adr_i[9]
  PIN wbs_cyc_i
    DIRECTION INPUT ;
    USE SIGNAL ;
    ANTENNAGATEAREA 0.213000 ;
    PORT
      LAYER met3 ;
        RECT 696.000 73.480 700.000 74.080 ;
    END
  END wbs_cyc_i
  PIN wbs_dat_i[0]
    DIRECTION INPUT ;
    USE SIGNAL ;
    ANTENNAGATEAREA 0.213000 ;
    PORT
      LAYER met3 ;
        RECT 696.000 84.360 700.000 84.960 ;
    END
  END wbs_dat_i[0]
  PIN wbs_dat_i[10]
    DIRECTION INPUT ;
    USE SIGNAL ;
    ANTENNAGATEAREA 0.213000 ;
    PORT
      LAYER met3 ;
        RECT 696.000 176.840 700.000 177.440 ;
    END
  END wbs_dat_i[10]
  PIN wbs_dat_i[11]
    DIRECTION INPUT ;
    USE SIGNAL ;
    ANTENNAGATEAREA 0.213000 ;
    PORT
      LAYER met3 ;
        RECT 696.000 185.000 700.000 185.600 ;
    END
  END wbs_dat_i[11]
  PIN wbs_dat_i[12]
    DIRECTION INPUT ;
    USE SIGNAL ;
    ANTENNAGATEAREA 0.213000 ;
    PORT
      LAYER met3 ;
        RECT 696.000 193.160 700.000 193.760 ;
    END
  END wbs_dat_i[12]
  PIN wbs_dat_i[13]
    DIRECTION INPUT ;
    USE SIGNAL ;
    ANTENNAGATEAREA 0.213000 ;
    PORT
      LAYER met3 ;
        RECT 696.000 201.320 700.000 201.920 ;
    END
  END wbs_dat_i[13]
  PIN wbs_dat_i[14]
    DIRECTION INPUT ;
    USE SIGNAL ;
    ANTENNAGATEAREA 0.213000 ;
    PORT
      LAYER met3 ;
        RECT 696.000 209.480 700.000 210.080 ;
    END
  END wbs_dat_i[14]
  PIN wbs_dat_i[15]
    DIRECTION INPUT ;
    USE SIGNAL ;
    ANTENNAGATEAREA 0.213000 ;
    PORT
      LAYER met3 ;
        RECT 696.000 217.640 700.000 218.240 ;
    END
  END wbs_dat_i[15]
  PIN wbs_dat_i[16]
    DIRECTION INPUT ;
    USE SIGNAL ;
    ANTENNAGATEAREA 0.213000 ;
    PORT
      LAYER met3 ;
        RECT 696.000 225.800 700.000 226.400 ;
    END
  END wbs_dat_i[16]
  PIN wbs_dat_i[17]
    DIRECTION INPUT ;
    USE SIGNAL ;
    ANTENNAGATEAREA 0.159000 ;
    PORT
      LAYER met3 ;
        RECT 696.000 233.960 700.000 234.560 ;
    END
  END wbs_dat_i[17]
  PIN wbs_dat_i[18]
    DIRECTION INPUT ;
    USE SIGNAL ;
    ANTENNAGATEAREA 0.213000 ;
    PORT
      LAYER met3 ;
        RECT 696.000 242.120 700.000 242.720 ;
    END
  END wbs_dat_i[18]
  PIN wbs_dat_i[19]
    DIRECTION INPUT ;
    USE SIGNAL ;
    ANTENNAGATEAREA 0.213000 ;
    PORT
      LAYER met3 ;
        RECT 696.000 250.280 700.000 250.880 ;
    END
  END wbs_dat_i[19]
  PIN wbs_dat_i[1]
    DIRECTION INPUT ;
    USE SIGNAL ;
    ANTENNAGATEAREA 0.213000 ;
    PORT
      LAYER met3 ;
        RECT 696.000 95.240 700.000 95.840 ;
    END
  END wbs_dat_i[1]
  PIN wbs_dat_i[20]
    DIRECTION INPUT ;
    USE SIGNAL ;
    ANTENNAGATEAREA 0.213000 ;
    PORT
      LAYER met3 ;
        RECT 696.000 258.440 700.000 259.040 ;
    END
  END wbs_dat_i[20]
  PIN wbs_dat_i[21]
    DIRECTION INPUT ;
    USE SIGNAL ;
    ANTENNAGATEAREA 0.213000 ;
    PORT
      LAYER met3 ;
        RECT 696.000 266.600 700.000 267.200 ;
    END
  END wbs_dat_i[21]
  PIN wbs_dat_i[22]
    DIRECTION INPUT ;
    USE SIGNAL ;
    ANTENNAGATEAREA 0.196500 ;
    PORT
      LAYER met3 ;
        RECT 696.000 274.760 700.000 275.360 ;
    END
  END wbs_dat_i[22]
  PIN wbs_dat_i[23]
    DIRECTION INPUT ;
    USE SIGNAL ;
    ANTENNAGATEAREA 0.126000 ;
    PORT
      LAYER met3 ;
        RECT 696.000 282.920 700.000 283.520 ;
    END
  END wbs_dat_i[23]
  PIN wbs_dat_i[24]
    DIRECTION INPUT ;
    USE SIGNAL ;
    ANTENNAGATEAREA 0.196500 ;
    PORT
      LAYER met3 ;
        RECT 696.000 291.080 700.000 291.680 ;
    END
  END wbs_dat_i[24]
  PIN wbs_dat_i[25]
    DIRECTION INPUT ;
    USE SIGNAL ;
    ANTENNAGATEAREA 0.196500 ;
    PORT
      LAYER met3 ;
        RECT 696.000 299.240 700.000 299.840 ;
    END
  END wbs_dat_i[25]
  PIN wbs_dat_i[26]
    DIRECTION INPUT ;
    USE SIGNAL ;
    ANTENNAGATEAREA 0.196500 ;
    PORT
      LAYER met3 ;
        RECT 696.000 307.400 700.000 308.000 ;
    END
  END wbs_dat_i[26]
  PIN wbs_dat_i[27]
    DIRECTION INPUT ;
    USE SIGNAL ;
    ANTENNAGATEAREA 0.196500 ;
    PORT
      LAYER met3 ;
        RECT 696.000 315.560 700.000 316.160 ;
    END
  END wbs_dat_i[27]
  PIN wbs_dat_i[28]
    DIRECTION INPUT ;
    USE SIGNAL ;
    ANTENNAGATEAREA 0.196500 ;
    PORT
      LAYER met3 ;
        RECT 696.000 323.720 700.000 324.320 ;
    END
  END wbs_dat_i[28]
  PIN wbs_dat_i[29]
    DIRECTION INPUT ;
    USE SIGNAL ;
    ANTENNAGATEAREA 0.196500 ;
    PORT
      LAYER met3 ;
        RECT 696.000 331.880 700.000 332.480 ;
    END
  END wbs_dat_i[29]
  PIN wbs_dat_i[2]
    DIRECTION INPUT ;
    USE SIGNAL ;
    ANTENNAGATEAREA 0.159000 ;
    PORT
      LAYER met3 ;
        RECT 696.000 106.120 700.000 106.720 ;
    END
  END wbs_dat_i[2]
  PIN wbs_dat_i[30]
    DIRECTION INPUT ;
    USE SIGNAL ;
    ANTENNAGATEAREA 0.196500 ;
    PORT
      LAYER met3 ;
        RECT 696.000 340.040 700.000 340.640 ;
    END
  END wbs_dat_i[30]
  PIN wbs_dat_i[31]
    DIRECTION INPUT ;
    USE SIGNAL ;
    ANTENNAGATEAREA 0.196500 ;
    PORT
      LAYER met3 ;
        RECT 696.000 348.200 700.000 348.800 ;
    END
  END wbs_dat_i[31]
  PIN wbs_dat_i[3]
    DIRECTION INPUT ;
    USE SIGNAL ;
    ANTENNAGATEAREA 0.213000 ;
    PORT
      LAYER met3 ;
        RECT 696.000 117.000 700.000 117.600 ;
    END
  END wbs_dat_i[3]
  PIN wbs_dat_i[4]
    DIRECTION INPUT ;
    USE SIGNAL ;
    ANTENNAGATEAREA 0.213000 ;
    PORT
      LAYER met3 ;
        RECT 696.000 127.880 700.000 128.480 ;
    END
  END wbs_dat_i[4]
  PIN wbs_dat_i[5]
    DIRECTION INPUT ;
    USE SIGNAL ;
    ANTENNAGATEAREA 0.213000 ;
    PORT
      LAYER met3 ;
        RECT 696.000 136.040 700.000 136.640 ;
    END
  END wbs_dat_i[5]
  PIN wbs_dat_i[6]
    DIRECTION INPUT ;
    USE SIGNAL ;
    ANTENNAGATEAREA 0.213000 ;
    PORT
      LAYER met3 ;
        RECT 696.000 144.200 700.000 144.800 ;
    END
  END wbs_dat_i[6]
  PIN wbs_dat_i[7]
    DIRECTION INPUT ;
    USE SIGNAL ;
    ANTENNAGATEAREA 0.213000 ;
    PORT
      LAYER met3 ;
        RECT 696.000 152.360 700.000 152.960 ;
    END
  END wbs_dat_i[7]
  PIN wbs_dat_i[8]
    DIRECTION INPUT ;
    USE SIGNAL ;
    ANTENNAGATEAREA 0.159000 ;
    PORT
      LAYER met3 ;
        RECT 696.000 160.520 700.000 161.120 ;
    END
  END wbs_dat_i[8]
  PIN wbs_dat_i[9]
    DIRECTION INPUT ;
    USE SIGNAL ;
    ANTENNAGATEAREA 0.213000 ;
    PORT
      LAYER met3 ;
        RECT 696.000 168.680 700.000 169.280 ;
    END
  END wbs_dat_i[9]
  PIN wbs_dat_o[0]
    DIRECTION OUTPUT TRISTATE ;
    USE SIGNAL ;
    ANTENNADIFFAREA 0.445500 ;
    PORT
      LAYER met3 ;
        RECT 696.000 87.080 700.000 87.680 ;
    END
  END wbs_dat_o[0]
  PIN wbs_dat_o[10]
    DIRECTION OUTPUT TRISTATE ;
    USE SIGNAL ;
    ANTENNADIFFAREA 0.795200 ;
    PORT
      LAYER met3 ;
        RECT 696.000 179.560 700.000 180.160 ;
    END
  END wbs_dat_o[10]
  PIN wbs_dat_o[11]
    DIRECTION OUTPUT TRISTATE ;
    USE SIGNAL ;
    ANTENNADIFFAREA 0.445500 ;
    PORT
      LAYER met3 ;
        RECT 696.000 187.720 700.000 188.320 ;
    END
  END wbs_dat_o[11]
  PIN wbs_dat_o[12]
    DIRECTION OUTPUT TRISTATE ;
    USE SIGNAL ;
    ANTENNADIFFAREA 0.445500 ;
    PORT
      LAYER met3 ;
        RECT 696.000 195.880 700.000 196.480 ;
    END
  END wbs_dat_o[12]
  PIN wbs_dat_o[13]
    DIRECTION OUTPUT TRISTATE ;
    USE SIGNAL ;
    ANTENNADIFFAREA 0.445500 ;
    PORT
      LAYER met3 ;
        RECT 696.000 204.040 700.000 204.640 ;
    END
  END wbs_dat_o[13]
  PIN wbs_dat_o[14]
    DIRECTION OUTPUT TRISTATE ;
    USE SIGNAL ;
    ANTENNADIFFAREA 0.795200 ;
    PORT
      LAYER met3 ;
        RECT 696.000 212.200 700.000 212.800 ;
    END
  END wbs_dat_o[14]
  PIN wbs_dat_o[15]
    DIRECTION OUTPUT TRISTATE ;
    USE SIGNAL ;
    ANTENNADIFFAREA 0.445500 ;
    PORT
      LAYER met3 ;
        RECT 696.000 220.360 700.000 220.960 ;
    END
  END wbs_dat_o[15]
  PIN wbs_dat_o[16]
    DIRECTION OUTPUT TRISTATE ;
    USE SIGNAL ;
    ANTENNADIFFAREA 0.795200 ;
    PORT
      LAYER met3 ;
        RECT 696.000 228.520 700.000 229.120 ;
    END
  END wbs_dat_o[16]
  PIN wbs_dat_o[17]
    DIRECTION OUTPUT TRISTATE ;
    USE SIGNAL ;
    ANTENNADIFFAREA 0.445500 ;
    PORT
      LAYER met3 ;
        RECT 696.000 236.680 700.000 237.280 ;
    END
  END wbs_dat_o[17]
  PIN wbs_dat_o[18]
    DIRECTION OUTPUT TRISTATE ;
    USE SIGNAL ;
    ANTENNADIFFAREA 0.445500 ;
    PORT
      LAYER met3 ;
        RECT 696.000 244.840 700.000 245.440 ;
    END
  END wbs_dat_o[18]
  PIN wbs_dat_o[19]
    DIRECTION OUTPUT TRISTATE ;
    USE SIGNAL ;
    ANTENNADIFFAREA 0.795200 ;
    PORT
      LAYER met3 ;
        RECT 696.000 253.000 700.000 253.600 ;
    END
  END wbs_dat_o[19]
  PIN wbs_dat_o[1]
    DIRECTION OUTPUT TRISTATE ;
    USE SIGNAL ;
    ANTENNADIFFAREA 0.795200 ;
    PORT
      LAYER met3 ;
        RECT 696.000 97.960 700.000 98.560 ;
    END
  END wbs_dat_o[1]
  PIN wbs_dat_o[20]
    DIRECTION OUTPUT TRISTATE ;
    USE SIGNAL ;
    ANTENNADIFFAREA 0.795200 ;
    PORT
      LAYER met3 ;
        RECT 696.000 261.160 700.000 261.760 ;
    END
  END wbs_dat_o[20]
  PIN wbs_dat_o[21]
    DIRECTION OUTPUT TRISTATE ;
    USE SIGNAL ;
    ANTENNADIFFAREA 0.445500 ;
    PORT
      LAYER met3 ;
        RECT 696.000 269.320 700.000 269.920 ;
    END
  END wbs_dat_o[21]
  PIN wbs_dat_o[22]
    DIRECTION OUTPUT TRISTATE ;
    USE SIGNAL ;
    ANTENNADIFFAREA 0.445500 ;
    PORT
      LAYER met3 ;
        RECT 696.000 277.480 700.000 278.080 ;
    END
  END wbs_dat_o[22]
  PIN wbs_dat_o[23]
    DIRECTION OUTPUT TRISTATE ;
    USE SIGNAL ;
    ANTENNADIFFAREA 0.445500 ;
    PORT
      LAYER met3 ;
        RECT 696.000 285.640 700.000 286.240 ;
    END
  END wbs_dat_o[23]
  PIN wbs_dat_o[24]
    DIRECTION OUTPUT TRISTATE ;
    USE SIGNAL ;
    ANTENNADIFFAREA 0.795200 ;
    PORT
      LAYER met3 ;
        RECT 696.000 293.800 700.000 294.400 ;
    END
  END wbs_dat_o[24]
  PIN wbs_dat_o[25]
    DIRECTION OUTPUT TRISTATE ;
    USE SIGNAL ;
    ANTENNADIFFAREA 0.445500 ;
    PORT
      LAYER met3 ;
        RECT 696.000 301.960 700.000 302.560 ;
    END
  END wbs_dat_o[25]
  PIN wbs_dat_o[26]
    DIRECTION OUTPUT TRISTATE ;
    USE SIGNAL ;
    ANTENNADIFFAREA 0.795200 ;
    PORT
      LAYER met3 ;
        RECT 696.000 310.120 700.000 310.720 ;
    END
  END wbs_dat_o[26]
  PIN wbs_dat_o[27]
    DIRECTION OUTPUT TRISTATE ;
    USE SIGNAL ;
    ANTENNADIFFAREA 0.445500 ;
    PORT
      LAYER met3 ;
        RECT 696.000 318.280 700.000 318.880 ;
    END
  END wbs_dat_o[27]
  PIN wbs_dat_o[28]
    DIRECTION OUTPUT TRISTATE ;
    USE SIGNAL ;
    ANTENNADIFFAREA 0.445500 ;
    PORT
      LAYER met3 ;
        RECT 696.000 326.440 700.000 327.040 ;
    END
  END wbs_dat_o[28]
  PIN wbs_dat_o[29]
    DIRECTION OUTPUT TRISTATE ;
    USE SIGNAL ;
    ANTENNADIFFAREA 0.795200 ;
    PORT
      LAYER met3 ;
        RECT 696.000 334.600 700.000 335.200 ;
    END
  END wbs_dat_o[29]
  PIN wbs_dat_o[2]
    DIRECTION OUTPUT TRISTATE ;
    USE SIGNAL ;
    ANTENNADIFFAREA 0.795200 ;
    PORT
      LAYER met3 ;
        RECT 696.000 108.840 700.000 109.440 ;
    END
  END wbs_dat_o[2]
  PIN wbs_dat_o[30]
    DIRECTION OUTPUT TRISTATE ;
    USE SIGNAL ;
    ANTENNADIFFAREA 0.445500 ;
    PORT
      LAYER met3 ;
        RECT 696.000 342.760 700.000 343.360 ;
    END
  END wbs_dat_o[30]
  PIN wbs_dat_o[31]
    DIRECTION OUTPUT TRISTATE ;
    USE SIGNAL ;
    ANTENNADIFFAREA 0.795200 ;
    PORT
      LAYER met3 ;
        RECT 696.000 350.920 700.000 351.520 ;
    END
  END wbs_dat_o[31]
  PIN wbs_dat_o[3]
    DIRECTION OUTPUT TRISTATE ;
    USE SIGNAL ;
    ANTENNADIFFAREA 0.445500 ;
    PORT
      LAYER met3 ;
        RECT 696.000 119.720 700.000 120.320 ;
    END
  END wbs_dat_o[3]
  PIN wbs_dat_o[4]
    DIRECTION OUTPUT TRISTATE ;
    USE SIGNAL ;
    ANTENNADIFFAREA 0.795200 ;
    PORT
      LAYER met3 ;
        RECT 696.000 130.600 700.000 131.200 ;
    END
  END wbs_dat_o[4]
  PIN wbs_dat_o[5]
    DIRECTION OUTPUT TRISTATE ;
    USE SIGNAL ;
    ANTENNADIFFAREA 0.795200 ;
    PORT
      LAYER met3 ;
        RECT 696.000 138.760 700.000 139.360 ;
    END
  END wbs_dat_o[5]
  PIN wbs_dat_o[6]
    DIRECTION OUTPUT TRISTATE ;
    USE SIGNAL ;
    ANTENNADIFFAREA 0.795200 ;
    PORT
      LAYER met3 ;
        RECT 696.000 146.920 700.000 147.520 ;
    END
  END wbs_dat_o[6]
  PIN wbs_dat_o[7]
    DIRECTION OUTPUT TRISTATE ;
    USE SIGNAL ;
    ANTENNADIFFAREA 0.795200 ;
    PORT
      LAYER met3 ;
        RECT 696.000 155.080 700.000 155.680 ;
    END
  END wbs_dat_o[7]
  PIN wbs_dat_o[8]
    DIRECTION OUTPUT TRISTATE ;
    USE SIGNAL ;
    ANTENNADIFFAREA 0.445500 ;
    PORT
      LAYER met3 ;
        RECT 696.000 163.240 700.000 163.840 ;
    END
  END wbs_dat_o[8]
  PIN wbs_dat_o[9]
    DIRECTION OUTPUT TRISTATE ;
    USE SIGNAL ;
    ANTENNADIFFAREA 0.795200 ;
    PORT
      LAYER met3 ;
        RECT 696.000 171.400 700.000 172.000 ;
    END
  END wbs_dat_o[9]
  PIN wbs_sel_i[0]
    DIRECTION INPUT ;
    USE SIGNAL ;
    PORT
      LAYER met3 ;
        RECT 696.000 89.800 700.000 90.400 ;
    END
  END wbs_sel_i[0]
  PIN wbs_sel_i[1]
    DIRECTION INPUT ;
    USE SIGNAL ;
    PORT
      LAYER met3 ;
        RECT 696.000 100.680 700.000 101.280 ;
    END
  END wbs_sel_i[1]
  PIN wbs_sel_i[2]
    DIRECTION INPUT ;
    USE SIGNAL ;
    PORT
      LAYER met3 ;
        RECT 696.000 111.560 700.000 112.160 ;
    END
  END wbs_sel_i[2]
  PIN wbs_sel_i[3]
    DIRECTION INPUT ;
    USE SIGNAL ;
    PORT
      LAYER met3 ;
        RECT 696.000 122.440 700.000 123.040 ;
    END
  END wbs_sel_i[3]
  PIN wbs_stb_i
    DIRECTION INPUT ;
    USE SIGNAL ;
    ANTENNAGATEAREA 0.213000 ;
    PORT
      LAYER met3 ;
        RECT 696.000 76.200 700.000 76.800 ;
    END
  END wbs_stb_i
  PIN wbs_we_i
    DIRECTION INPUT ;
    USE SIGNAL ;
    ANTENNAGATEAREA 0.213000 ;
    PORT
      LAYER met3 ;
        RECT 696.000 78.920 700.000 79.520 ;
    END
  END wbs_we_i
  OBS
      LAYER li1 ;
        RECT 5.520 10.795 694.140 438.005 ;
      LAYER met1 ;
        RECT 4.670 10.640 697.290 438.160 ;
      LAYER met2 ;
        RECT 4.690 10.695 697.260 438.105 ;
      LAYER met3 ;
        RECT 3.990 433.520 696.000 438.085 ;
        RECT 4.400 432.120 696.000 433.520 ;
        RECT 3.990 429.440 696.000 432.120 ;
        RECT 4.400 428.040 696.000 429.440 ;
        RECT 3.990 425.360 696.000 428.040 ;
        RECT 4.400 423.960 696.000 425.360 ;
        RECT 3.990 421.280 696.000 423.960 ;
        RECT 4.400 419.880 696.000 421.280 ;
        RECT 3.990 417.200 696.000 419.880 ;
        RECT 4.400 415.800 696.000 417.200 ;
        RECT 3.990 413.120 696.000 415.800 ;
        RECT 4.400 411.720 696.000 413.120 ;
        RECT 3.990 409.040 696.000 411.720 ;
        RECT 4.400 407.640 696.000 409.040 ;
        RECT 3.990 404.960 696.000 407.640 ;
        RECT 4.400 403.560 696.000 404.960 ;
        RECT 3.990 400.880 696.000 403.560 ;
        RECT 4.400 399.480 696.000 400.880 ;
        RECT 3.990 396.800 696.000 399.480 ;
        RECT 4.400 395.400 696.000 396.800 ;
        RECT 3.990 392.720 696.000 395.400 ;
        RECT 4.400 391.320 696.000 392.720 ;
        RECT 3.990 388.640 696.000 391.320 ;
        RECT 4.400 387.240 696.000 388.640 ;
        RECT 3.990 384.560 696.000 387.240 ;
        RECT 4.400 383.160 695.600 384.560 ;
        RECT 3.990 381.840 696.000 383.160 ;
        RECT 3.990 380.480 695.600 381.840 ;
        RECT 4.400 380.440 695.600 380.480 ;
        RECT 4.400 379.120 696.000 380.440 ;
        RECT 4.400 379.080 695.600 379.120 ;
        RECT 3.990 377.720 695.600 379.080 ;
        RECT 3.990 376.400 696.000 377.720 ;
        RECT 4.400 375.000 695.600 376.400 ;
        RECT 3.990 373.680 696.000 375.000 ;
        RECT 3.990 372.320 695.600 373.680 ;
        RECT 4.400 372.280 695.600 372.320 ;
        RECT 4.400 370.960 696.000 372.280 ;
        RECT 4.400 370.920 695.600 370.960 ;
        RECT 3.990 369.560 695.600 370.920 ;
        RECT 3.990 368.240 696.000 369.560 ;
        RECT 4.400 366.840 695.600 368.240 ;
        RECT 3.990 365.520 696.000 366.840 ;
        RECT 3.990 364.160 695.600 365.520 ;
        RECT 4.400 364.120 695.600 364.160 ;
        RECT 4.400 362.800 696.000 364.120 ;
        RECT 4.400 362.760 695.600 362.800 ;
        RECT 3.990 361.400 695.600 362.760 ;
        RECT 3.990 360.080 696.000 361.400 ;
        RECT 4.400 358.680 695.600 360.080 ;
        RECT 3.990 357.360 696.000 358.680 ;
        RECT 3.990 356.000 695.600 357.360 ;
        RECT 4.400 355.960 695.600 356.000 ;
        RECT 4.400 354.640 696.000 355.960 ;
        RECT 4.400 354.600 695.600 354.640 ;
        RECT 3.990 353.240 695.600 354.600 ;
        RECT 3.990 351.920 696.000 353.240 ;
        RECT 4.400 350.520 695.600 351.920 ;
        RECT 3.990 349.200 696.000 350.520 ;
        RECT 3.990 347.840 695.600 349.200 ;
        RECT 4.400 347.800 695.600 347.840 ;
        RECT 4.400 346.480 696.000 347.800 ;
        RECT 4.400 346.440 695.600 346.480 ;
        RECT 3.990 345.080 695.600 346.440 ;
        RECT 3.990 343.760 696.000 345.080 ;
        RECT 4.400 342.360 695.600 343.760 ;
        RECT 3.990 341.040 696.000 342.360 ;
        RECT 3.990 339.680 695.600 341.040 ;
        RECT 4.400 339.640 695.600 339.680 ;
        RECT 4.400 338.320 696.000 339.640 ;
        RECT 4.400 338.280 695.600 338.320 ;
        RECT 3.990 336.920 695.600 338.280 ;
        RECT 3.990 335.600 696.000 336.920 ;
        RECT 4.400 334.200 695.600 335.600 ;
        RECT 3.990 332.880 696.000 334.200 ;
        RECT 3.990 331.520 695.600 332.880 ;
        RECT 4.400 331.480 695.600 331.520 ;
        RECT 4.400 330.160 696.000 331.480 ;
        RECT 4.400 330.120 695.600 330.160 ;
        RECT 3.990 328.760 695.600 330.120 ;
        RECT 3.990 327.440 696.000 328.760 ;
        RECT 4.400 326.040 695.600 327.440 ;
        RECT 3.990 324.720 696.000 326.040 ;
        RECT 3.990 323.360 695.600 324.720 ;
        RECT 4.400 323.320 695.600 323.360 ;
        RECT 4.400 322.000 696.000 323.320 ;
        RECT 4.400 321.960 695.600 322.000 ;
        RECT 3.990 320.600 695.600 321.960 ;
        RECT 3.990 319.280 696.000 320.600 ;
        RECT 4.400 317.880 695.600 319.280 ;
        RECT 3.990 316.560 696.000 317.880 ;
        RECT 3.990 315.200 695.600 316.560 ;
        RECT 4.400 315.160 695.600 315.200 ;
        RECT 4.400 313.840 696.000 315.160 ;
        RECT 4.400 313.800 695.600 313.840 ;
        RECT 3.990 312.440 695.600 313.800 ;
        RECT 3.990 311.120 696.000 312.440 ;
        RECT 4.400 309.720 695.600 311.120 ;
        RECT 3.990 308.400 696.000 309.720 ;
        RECT 3.990 307.040 695.600 308.400 ;
        RECT 4.400 307.000 695.600 307.040 ;
        RECT 4.400 305.680 696.000 307.000 ;
        RECT 4.400 305.640 695.600 305.680 ;
        RECT 3.990 304.280 695.600 305.640 ;
        RECT 3.990 302.960 696.000 304.280 ;
        RECT 4.400 301.560 695.600 302.960 ;
        RECT 3.990 300.240 696.000 301.560 ;
        RECT 3.990 298.880 695.600 300.240 ;
        RECT 4.400 298.840 695.600 298.880 ;
        RECT 4.400 297.520 696.000 298.840 ;
        RECT 4.400 297.480 695.600 297.520 ;
        RECT 3.990 296.120 695.600 297.480 ;
        RECT 3.990 294.800 696.000 296.120 ;
        RECT 4.400 293.400 695.600 294.800 ;
        RECT 3.990 292.080 696.000 293.400 ;
        RECT 3.990 290.720 695.600 292.080 ;
        RECT 4.400 290.680 695.600 290.720 ;
        RECT 4.400 289.360 696.000 290.680 ;
        RECT 4.400 289.320 695.600 289.360 ;
        RECT 3.990 287.960 695.600 289.320 ;
        RECT 3.990 286.640 696.000 287.960 ;
        RECT 4.400 285.240 695.600 286.640 ;
        RECT 3.990 283.920 696.000 285.240 ;
        RECT 3.990 282.560 695.600 283.920 ;
        RECT 4.400 282.520 695.600 282.560 ;
        RECT 4.400 281.200 696.000 282.520 ;
        RECT 4.400 281.160 695.600 281.200 ;
        RECT 3.990 279.800 695.600 281.160 ;
        RECT 3.990 278.480 696.000 279.800 ;
        RECT 4.400 277.080 695.600 278.480 ;
        RECT 3.990 275.760 696.000 277.080 ;
        RECT 3.990 274.400 695.600 275.760 ;
        RECT 4.400 274.360 695.600 274.400 ;
        RECT 4.400 273.040 696.000 274.360 ;
        RECT 4.400 273.000 695.600 273.040 ;
        RECT 3.990 271.640 695.600 273.000 ;
        RECT 3.990 270.320 696.000 271.640 ;
        RECT 4.400 268.920 695.600 270.320 ;
        RECT 3.990 267.600 696.000 268.920 ;
        RECT 3.990 266.240 695.600 267.600 ;
        RECT 4.400 266.200 695.600 266.240 ;
        RECT 4.400 264.880 696.000 266.200 ;
        RECT 4.400 264.840 695.600 264.880 ;
        RECT 3.990 263.480 695.600 264.840 ;
        RECT 3.990 262.160 696.000 263.480 ;
        RECT 4.400 260.760 695.600 262.160 ;
        RECT 3.990 259.440 696.000 260.760 ;
        RECT 3.990 258.080 695.600 259.440 ;
        RECT 4.400 258.040 695.600 258.080 ;
        RECT 4.400 256.720 696.000 258.040 ;
        RECT 4.400 256.680 695.600 256.720 ;
        RECT 3.990 255.320 695.600 256.680 ;
        RECT 3.990 254.000 696.000 255.320 ;
        RECT 4.400 252.600 695.600 254.000 ;
        RECT 3.990 251.280 696.000 252.600 ;
        RECT 3.990 249.920 695.600 251.280 ;
        RECT 4.400 249.880 695.600 249.920 ;
        RECT 4.400 248.560 696.000 249.880 ;
        RECT 4.400 248.520 695.600 248.560 ;
        RECT 3.990 247.160 695.600 248.520 ;
        RECT 3.990 245.840 696.000 247.160 ;
        RECT 4.400 244.440 695.600 245.840 ;
        RECT 3.990 243.120 696.000 244.440 ;
        RECT 3.990 241.760 695.600 243.120 ;
        RECT 4.400 241.720 695.600 241.760 ;
        RECT 4.400 240.400 696.000 241.720 ;
        RECT 4.400 240.360 695.600 240.400 ;
        RECT 3.990 239.000 695.600 240.360 ;
        RECT 3.990 237.680 696.000 239.000 ;
        RECT 4.400 236.280 695.600 237.680 ;
        RECT 3.990 234.960 696.000 236.280 ;
        RECT 3.990 233.600 695.600 234.960 ;
        RECT 4.400 233.560 695.600 233.600 ;
        RECT 4.400 232.240 696.000 233.560 ;
        RECT 4.400 232.200 695.600 232.240 ;
        RECT 3.990 230.840 695.600 232.200 ;
        RECT 3.990 229.520 696.000 230.840 ;
        RECT 4.400 228.120 695.600 229.520 ;
        RECT 3.990 226.800 696.000 228.120 ;
        RECT 3.990 225.440 695.600 226.800 ;
        RECT 4.400 225.400 695.600 225.440 ;
        RECT 4.400 224.080 696.000 225.400 ;
        RECT 4.400 224.040 695.600 224.080 ;
        RECT 3.990 222.680 695.600 224.040 ;
        RECT 3.990 221.360 696.000 222.680 ;
        RECT 4.400 219.960 695.600 221.360 ;
        RECT 3.990 218.640 696.000 219.960 ;
        RECT 3.990 217.280 695.600 218.640 ;
        RECT 4.400 217.240 695.600 217.280 ;
        RECT 4.400 215.920 696.000 217.240 ;
        RECT 4.400 215.880 695.600 215.920 ;
        RECT 3.990 214.520 695.600 215.880 ;
        RECT 3.990 213.200 696.000 214.520 ;
        RECT 4.400 211.800 695.600 213.200 ;
        RECT 3.990 210.480 696.000 211.800 ;
        RECT 3.990 209.120 695.600 210.480 ;
        RECT 4.400 209.080 695.600 209.120 ;
        RECT 4.400 207.760 696.000 209.080 ;
        RECT 4.400 207.720 695.600 207.760 ;
        RECT 3.990 206.360 695.600 207.720 ;
        RECT 3.990 205.040 696.000 206.360 ;
        RECT 4.400 203.640 695.600 205.040 ;
        RECT 3.990 202.320 696.000 203.640 ;
        RECT 3.990 200.960 695.600 202.320 ;
        RECT 4.400 200.920 695.600 200.960 ;
        RECT 4.400 199.600 696.000 200.920 ;
        RECT 4.400 199.560 695.600 199.600 ;
        RECT 3.990 198.200 695.600 199.560 ;
        RECT 3.990 196.880 696.000 198.200 ;
        RECT 4.400 195.480 695.600 196.880 ;
        RECT 3.990 194.160 696.000 195.480 ;
        RECT 3.990 192.800 695.600 194.160 ;
        RECT 4.400 192.760 695.600 192.800 ;
        RECT 4.400 191.440 696.000 192.760 ;
        RECT 4.400 191.400 695.600 191.440 ;
        RECT 3.990 190.040 695.600 191.400 ;
        RECT 3.990 188.720 696.000 190.040 ;
        RECT 4.400 187.320 695.600 188.720 ;
        RECT 3.990 186.000 696.000 187.320 ;
        RECT 3.990 184.640 695.600 186.000 ;
        RECT 4.400 184.600 695.600 184.640 ;
        RECT 4.400 183.280 696.000 184.600 ;
        RECT 4.400 183.240 695.600 183.280 ;
        RECT 3.990 181.880 695.600 183.240 ;
        RECT 3.990 180.560 696.000 181.880 ;
        RECT 4.400 179.160 695.600 180.560 ;
        RECT 3.990 177.840 696.000 179.160 ;
        RECT 3.990 176.480 695.600 177.840 ;
        RECT 4.400 176.440 695.600 176.480 ;
        RECT 4.400 175.120 696.000 176.440 ;
        RECT 4.400 175.080 695.600 175.120 ;
        RECT 3.990 173.720 695.600 175.080 ;
        RECT 3.990 172.400 696.000 173.720 ;
        RECT 4.400 171.000 695.600 172.400 ;
        RECT 3.990 169.680 696.000 171.000 ;
        RECT 3.990 168.320 695.600 169.680 ;
        RECT 4.400 168.280 695.600 168.320 ;
        RECT 4.400 166.960 696.000 168.280 ;
        RECT 4.400 166.920 695.600 166.960 ;
        RECT 3.990 165.560 695.600 166.920 ;
        RECT 3.990 164.240 696.000 165.560 ;
        RECT 4.400 162.840 695.600 164.240 ;
        RECT 3.990 161.520 696.000 162.840 ;
        RECT 3.990 160.160 695.600 161.520 ;
        RECT 4.400 160.120 695.600 160.160 ;
        RECT 4.400 158.800 696.000 160.120 ;
        RECT 4.400 158.760 695.600 158.800 ;
        RECT 3.990 157.400 695.600 158.760 ;
        RECT 3.990 156.080 696.000 157.400 ;
        RECT 4.400 154.680 695.600 156.080 ;
        RECT 3.990 153.360 696.000 154.680 ;
        RECT 3.990 152.000 695.600 153.360 ;
        RECT 4.400 151.960 695.600 152.000 ;
        RECT 4.400 150.640 696.000 151.960 ;
        RECT 4.400 150.600 695.600 150.640 ;
        RECT 3.990 149.240 695.600 150.600 ;
        RECT 3.990 147.920 696.000 149.240 ;
        RECT 4.400 146.520 695.600 147.920 ;
        RECT 3.990 145.200 696.000 146.520 ;
        RECT 3.990 143.840 695.600 145.200 ;
        RECT 4.400 143.800 695.600 143.840 ;
        RECT 4.400 142.480 696.000 143.800 ;
        RECT 4.400 142.440 695.600 142.480 ;
        RECT 3.990 141.080 695.600 142.440 ;
        RECT 3.990 139.760 696.000 141.080 ;
        RECT 4.400 138.360 695.600 139.760 ;
        RECT 3.990 137.040 696.000 138.360 ;
        RECT 3.990 135.680 695.600 137.040 ;
        RECT 4.400 135.640 695.600 135.680 ;
        RECT 4.400 134.320 696.000 135.640 ;
        RECT 4.400 134.280 695.600 134.320 ;
        RECT 3.990 132.920 695.600 134.280 ;
        RECT 3.990 131.600 696.000 132.920 ;
        RECT 4.400 130.200 695.600 131.600 ;
        RECT 3.990 128.880 696.000 130.200 ;
        RECT 3.990 127.520 695.600 128.880 ;
        RECT 4.400 127.480 695.600 127.520 ;
        RECT 4.400 126.160 696.000 127.480 ;
        RECT 4.400 126.120 695.600 126.160 ;
        RECT 3.990 124.760 695.600 126.120 ;
        RECT 3.990 123.440 696.000 124.760 ;
        RECT 4.400 122.040 695.600 123.440 ;
        RECT 3.990 120.720 696.000 122.040 ;
        RECT 3.990 119.360 695.600 120.720 ;
        RECT 4.400 119.320 695.600 119.360 ;
        RECT 4.400 118.000 696.000 119.320 ;
        RECT 4.400 117.960 695.600 118.000 ;
        RECT 3.990 116.600 695.600 117.960 ;
        RECT 3.990 115.280 696.000 116.600 ;
        RECT 4.400 113.880 695.600 115.280 ;
        RECT 3.990 112.560 696.000 113.880 ;
        RECT 3.990 111.200 695.600 112.560 ;
        RECT 4.400 111.160 695.600 111.200 ;
        RECT 4.400 109.840 696.000 111.160 ;
        RECT 4.400 109.800 695.600 109.840 ;
        RECT 3.990 108.440 695.600 109.800 ;
        RECT 3.990 107.120 696.000 108.440 ;
        RECT 4.400 105.720 695.600 107.120 ;
        RECT 3.990 104.400 696.000 105.720 ;
        RECT 3.990 103.040 695.600 104.400 ;
        RECT 4.400 103.000 695.600 103.040 ;
        RECT 4.400 101.680 696.000 103.000 ;
        RECT 4.400 101.640 695.600 101.680 ;
        RECT 3.990 100.280 695.600 101.640 ;
        RECT 3.990 98.960 696.000 100.280 ;
        RECT 4.400 97.560 695.600 98.960 ;
        RECT 3.990 96.240 696.000 97.560 ;
        RECT 3.990 94.880 695.600 96.240 ;
        RECT 4.400 94.840 695.600 94.880 ;
        RECT 4.400 93.520 696.000 94.840 ;
        RECT 4.400 93.480 695.600 93.520 ;
        RECT 3.990 92.120 695.600 93.480 ;
        RECT 3.990 90.800 696.000 92.120 ;
        RECT 4.400 89.400 695.600 90.800 ;
        RECT 3.990 88.080 696.000 89.400 ;
        RECT 3.990 86.720 695.600 88.080 ;
        RECT 4.400 86.680 695.600 86.720 ;
        RECT 4.400 85.360 696.000 86.680 ;
        RECT 4.400 85.320 695.600 85.360 ;
        RECT 3.990 83.960 695.600 85.320 ;
        RECT 3.990 82.640 696.000 83.960 ;
        RECT 4.400 81.240 695.600 82.640 ;
        RECT 3.990 79.920 696.000 81.240 ;
        RECT 3.990 78.560 695.600 79.920 ;
        RECT 4.400 78.520 695.600 78.560 ;
        RECT 4.400 77.200 696.000 78.520 ;
        RECT 4.400 77.160 695.600 77.200 ;
        RECT 3.990 75.800 695.600 77.160 ;
        RECT 3.990 74.480 696.000 75.800 ;
        RECT 4.400 73.080 695.600 74.480 ;
        RECT 3.990 71.760 696.000 73.080 ;
        RECT 3.990 70.400 695.600 71.760 ;
        RECT 4.400 70.360 695.600 70.400 ;
        RECT 4.400 69.040 696.000 70.360 ;
        RECT 4.400 69.000 695.600 69.040 ;
        RECT 3.990 67.640 695.600 69.000 ;
        RECT 3.990 66.320 696.000 67.640 ;
        RECT 4.400 64.920 695.600 66.320 ;
        RECT 3.990 62.240 696.000 64.920 ;
        RECT 4.400 60.840 696.000 62.240 ;
        RECT 3.990 58.160 696.000 60.840 ;
        RECT 4.400 56.760 696.000 58.160 ;
        RECT 3.990 54.080 696.000 56.760 ;
        RECT 4.400 52.680 696.000 54.080 ;
        RECT 3.990 50.000 696.000 52.680 ;
        RECT 4.400 48.600 696.000 50.000 ;
        RECT 3.990 45.920 696.000 48.600 ;
        RECT 4.400 44.520 696.000 45.920 ;
        RECT 3.990 41.840 696.000 44.520 ;
        RECT 4.400 40.440 696.000 41.840 ;
        RECT 3.990 37.760 696.000 40.440 ;
        RECT 4.400 36.360 696.000 37.760 ;
        RECT 3.990 33.680 696.000 36.360 ;
        RECT 4.400 32.280 696.000 33.680 ;
        RECT 3.990 29.600 696.000 32.280 ;
        RECT 4.400 28.200 696.000 29.600 ;
        RECT 3.990 25.520 696.000 28.200 ;
        RECT 4.400 24.120 696.000 25.520 ;
        RECT 3.990 21.440 696.000 24.120 ;
        RECT 4.400 20.040 696.000 21.440 ;
        RECT 3.990 17.360 696.000 20.040 ;
        RECT 4.400 15.960 696.000 17.360 ;
        RECT 3.990 10.715 696.000 15.960 ;
      LAYER met4 ;
        RECT 19.615 43.695 20.640 386.745 ;
        RECT 23.040 43.695 23.940 386.745 ;
        RECT 26.340 43.695 174.240 386.745 ;
        RECT 176.640 43.695 177.540 386.745 ;
        RECT 179.940 43.695 327.840 386.745 ;
        RECT 330.240 43.695 331.140 386.745 ;
        RECT 333.540 43.695 481.440 386.745 ;
        RECT 483.840 43.695 484.740 386.745 ;
        RECT 487.140 43.695 635.040 386.745 ;
        RECT 637.440 43.695 638.340 386.745 ;
        RECT 640.740 43.695 667.625 386.745 ;
  END
END vga_wrapper_m
END LIBRARY

